VERSION 5.7 ;
  NOWIREEXTENSIONATPIN ON ;
  DIVIDERCHAR "/" ;
  BUSBITCHARS "[]" ;
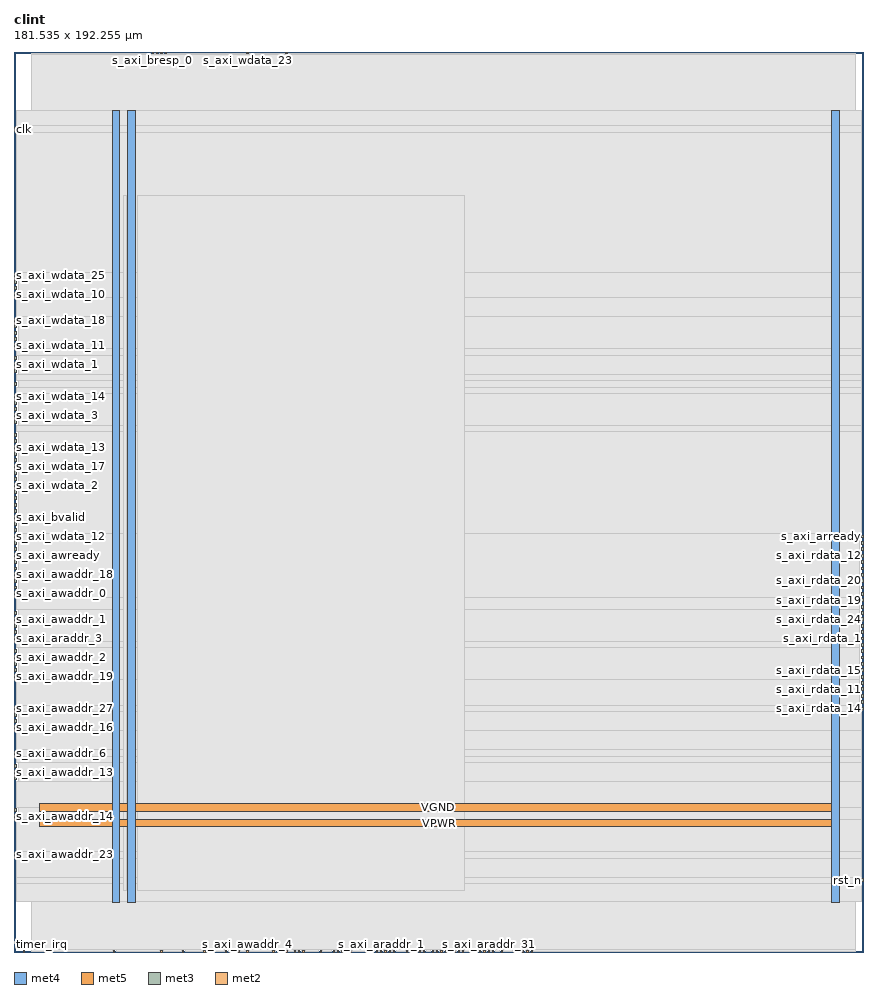
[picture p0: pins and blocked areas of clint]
MACRO clint
  CLASS BLOCK ;
  FOREIGN clint ;
  ORIGIN 0.000 0.000 ;
  SIZE 181.535 BY 192.255 ;
  PIN VGND
    DIRECTION INOUT ;
    USE GROUND ;
    PORT
      LAYER met4 ;
        RECT 24.340 10.640 25.940 179.760 ;
    END
    PORT
      LAYER met5 ;
        RECT 5.520 30.030 175.720 31.630 ;
    END
  END VGND
  PIN VPWR
    DIRECTION INOUT ;
    USE POWER ;
    PORT
      LAYER met4 ;
        RECT 21.040 10.640 22.640 179.760 ;
    END
    PORT
      LAYER met4 ;
        RECT 174.640 10.640 176.240 179.760 ;
    END
    PORT
      LAYER met5 ;
        RECT 5.520 26.730 176.240 28.330 ;
    END
  END VPWR
  PIN clk
    DIRECTION INPUT ;
    USE SIGNAL ;
    ANTENNAGATEAREA 1.286700 ;
    ANTENNADIFFAREA 0.434700 ;
    PORT
      LAYER met3 ;
        RECT 0.000 175.480 0.600 176.080 ;
    END
  END clk
  PIN rst_n
    DIRECTION INPUT ;
    USE SIGNAL ;
    ANTENNAGATEAREA 0.647700 ;
    ANTENNADIFFAREA 0.434700 ;
    PORT
      LAYER met3 ;
        RECT 180.935 15.000 181.535 15.600 ;
    END
  END rst_n
  PIN s_axi_araddr_0
    DIRECTION INPUT ;
    USE SIGNAL ;
    ANTENNAGATEAREA 0.647700 ;
    ANTENNADIFFAREA 0.434700 ;
    PORT
      LAYER met2 ;
        RECT 68.170 0.000 68.450 0.280 ;
    END
  END s_axi_araddr_0
  PIN s_axi_araddr_1
    DIRECTION INPUT ;
    USE SIGNAL ;
    ANTENNAGATEAREA 0.647700 ;
    ANTENNADIFFAREA 0.434700 ;
    PORT
      LAYER met2 ;
        RECT 78.290 0.000 78.570 0.280 ;
    END
  END s_axi_araddr_1
  PIN s_axi_araddr_10
    DIRECTION INPUT ;
    USE SIGNAL ;
    ANTENNAGATEAREA 0.647700 ;
    ANTENNADIFFAREA 0.434700 ;
    PORT
      LAYER met2 ;
        RECT 65.410 0.000 65.690 0.280 ;
    END
  END s_axi_araddr_10
  PIN s_axi_araddr_11
    DIRECTION INPUT ;
    USE SIGNAL ;
    ANTENNAGATEAREA 0.647700 ;
    ANTENNADIFFAREA 0.434700 ;
    PORT
      LAYER met2 ;
        RECT 77.370 0.000 77.650 0.280 ;
    END
  END s_axi_araddr_11
  PIN s_axi_araddr_12
    DIRECTION INPUT ;
    USE SIGNAL ;
    ANTENNAGATEAREA 0.647700 ;
    ANTENNADIFFAREA 0.434700 ;
    PORT
      LAYER met2 ;
        RECT 79.210 0.000 79.490 0.280 ;
    END
  END s_axi_araddr_12
  PIN s_axi_araddr_13
    DIRECTION INPUT ;
    USE SIGNAL ;
    ANTENNAGATEAREA 0.647700 ;
    ANTENNADIFFAREA 0.434700 ;
    PORT
      LAYER met2 ;
        RECT 70.010 0.000 70.290 0.280 ;
    END
  END s_axi_araddr_13
  PIN s_axi_araddr_14
    DIRECTION INPUT ;
    USE SIGNAL ;
    ANTENNAGATEAREA 0.647700 ;
    ANTENNADIFFAREA 0.434700 ;
    PORT
      LAYER met2 ;
        RECT 61.730 0.000 62.010 0.280 ;
    END
  END s_axi_araddr_14
  PIN s_axi_araddr_15
    DIRECTION INPUT ;
    USE SIGNAL ;
    ANTENNAGATEAREA 0.647700 ;
    ANTENNADIFFAREA 0.434700 ;
    PORT
      LAYER met2 ;
        RECT 55.290 0.000 55.570 0.280 ;
    END
  END s_axi_araddr_15
  PIN s_axi_araddr_16
    DIRECTION INPUT ;
    USE SIGNAL ;
    ANTENNAGATEAREA 0.647700 ;
    ANTENNADIFFAREA 0.434700 ;
    PORT
      LAYER met2 ;
        RECT 89.330 0.000 89.610 0.280 ;
    END
  END s_axi_araddr_16
  PIN s_axi_araddr_17
    DIRECTION INPUT ;
    USE SIGNAL ;
    ANTENNAGATEAREA 0.647700 ;
    ANTENNADIFFAREA 0.434700 ;
    PORT
      LAYER met2 ;
        RECT 110.490 0.000 110.770 0.280 ;
    END
  END s_axi_araddr_17
  PIN s_axi_araddr_18
    DIRECTION INPUT ;
    USE SIGNAL ;
    ANTENNAGATEAREA 0.647700 ;
    ANTENNADIFFAREA 0.434700 ;
    PORT
      LAYER met2 ;
        RECT 87.490 0.000 87.770 0.280 ;
    END
  END s_axi_araddr_18
  PIN s_axi_araddr_19
    DIRECTION INPUT ;
    USE SIGNAL ;
    ANTENNAGATEAREA 0.647700 ;
    ANTENNADIFFAREA 0.434700 ;
    PORT
      LAYER met2 ;
        RECT 104.050 0.000 104.330 0.280 ;
    END
  END s_axi_araddr_19
  PIN s_axi_araddr_2
    DIRECTION INPUT ;
    USE SIGNAL ;
    ANTENNAGATEAREA 0.647700 ;
    ANTENNADIFFAREA 0.434700 ;
    PORT
      LAYER met2 ;
        RECT 71.850 0.000 72.130 0.280 ;
    END
  END s_axi_araddr_2
  PIN s_axi_araddr_20
    DIRECTION INPUT ;
    USE SIGNAL ;
    ANTENNAGATEAREA 0.647700 ;
    ANTENNADIFFAREA 0.434700 ;
    PORT
      LAYER met2 ;
        RECT 80.130 0.000 80.410 0.280 ;
    END
  END s_axi_araddr_20
  PIN s_axi_araddr_21
    DIRECTION INPUT ;
    USE SIGNAL ;
    ANTENNAGATEAREA 0.647700 ;
    ANTENNADIFFAREA 0.434700 ;
    PORT
      LAYER met2 ;
        RECT 95.770 0.000 96.050 0.280 ;
    END
  END s_axi_araddr_21
  PIN s_axi_araddr_22
    DIRECTION INPUT ;
    USE SIGNAL ;
    ANTENNAGATEAREA 0.647700 ;
    ANTENNADIFFAREA 0.434700 ;
    PORT
      LAYER met2 ;
        RECT 99.450 0.000 99.730 0.280 ;
    END
  END s_axi_araddr_22
  PIN s_axi_araddr_23
    DIRECTION INPUT ;
    USE SIGNAL ;
    ANTENNAGATEAREA 0.647700 ;
    ANTENNADIFFAREA 0.434700 ;
    PORT
      LAYER met2 ;
        RECT 100.370 0.000 100.650 0.280 ;
    END
  END s_axi_araddr_23
  PIN s_axi_araddr_24
    DIRECTION INPUT ;
    USE SIGNAL ;
    ANTENNAGATEAREA 0.647700 ;
    ANTENNADIFFAREA 0.434700 ;
    PORT
      LAYER met2 ;
        RECT 86.570 0.000 86.850 0.280 ;
    END
  END s_axi_araddr_24
  PIN s_axi_araddr_25
    DIRECTION INPUT ;
    USE SIGNAL ;
    ANTENNAGATEAREA 0.647700 ;
    ANTENNADIFFAREA 0.434700 ;
    PORT
      LAYER met2 ;
        RECT 109.570 0.000 109.850 0.280 ;
    END
  END s_axi_araddr_25
  PIN s_axi_araddr_26
    DIRECTION INPUT ;
    USE SIGNAL ;
    ANTENNAGATEAREA 0.647700 ;
    ANTENNADIFFAREA 0.434700 ;
    PORT
      LAYER met2 ;
        RECT 106.810 0.000 107.090 0.280 ;
    END
  END s_axi_araddr_26
  PIN s_axi_araddr_27
    DIRECTION INPUT ;
    USE SIGNAL ;
    ANTENNAGATEAREA 0.647700 ;
    ANTENNADIFFAREA 0.434700 ;
    PORT
      LAYER met2 ;
        RECT 81.050 0.000 81.330 0.280 ;
    END
  END s_axi_araddr_27
  PIN s_axi_araddr_28
    DIRECTION INPUT ;
    USE SIGNAL ;
    ANTENNAGATEAREA 0.647700 ;
    ANTENNADIFFAREA 0.434700 ;
    PORT
      LAYER met2 ;
        RECT 90.250 0.000 90.530 0.280 ;
    END
  END s_axi_araddr_28
  PIN s_axi_araddr_29
    DIRECTION INPUT ;
    USE SIGNAL ;
    ANTENNAGATEAREA 0.647700 ;
    ANTENNADIFFAREA 0.434700 ;
    PORT
      LAYER met2 ;
        RECT 108.650 0.000 108.930 0.280 ;
    END
  END s_axi_araddr_29
  PIN s_axi_araddr_3
    DIRECTION INPUT ;
    USE SIGNAL ;
    ANTENNAGATEAREA 0.647700 ;
    ANTENNADIFFAREA 0.434700 ;
    PORT
      LAYER met3 ;
        RECT 0.000 66.680 0.600 67.280 ;
    END
  END s_axi_araddr_3
  PIN s_axi_araddr_30
    DIRECTION INPUT ;
    USE SIGNAL ;
    ANTENNAGATEAREA 0.647700 ;
    ANTENNADIFFAREA 0.434700 ;
    PORT
      LAYER met2 ;
        RECT 98.530 0.000 98.810 0.280 ;
    END
  END s_axi_araddr_30
  PIN s_axi_araddr_31
    DIRECTION INPUT ;
    USE SIGNAL ;
    ANTENNAGATEAREA 0.647700 ;
    ANTENNADIFFAREA 0.434700 ;
    PORT
      LAYER met2 ;
        RECT 101.290 0.000 101.570 0.280 ;
    END
  END s_axi_araddr_31
  PIN s_axi_araddr_4
    DIRECTION INPUT ;
    USE SIGNAL ;
    ANTENNAGATEAREA 0.647700 ;
    ANTENNADIFFAREA 0.434700 ;
    PORT
      LAYER met2 ;
        RECT 60.810 0.000 61.090 0.280 ;
    END
  END s_axi_araddr_4
  PIN s_axi_araddr_5
    DIRECTION INPUT ;
    USE SIGNAL ;
    ANTENNAGATEAREA 0.647700 ;
    ANTENNADIFFAREA 0.434700 ;
    PORT
      LAYER met2 ;
        RECT 59.890 0.000 60.170 0.280 ;
    END
  END s_axi_araddr_5
  PIN s_axi_araddr_6
    DIRECTION INPUT ;
    USE SIGNAL ;
    ANTENNAGATEAREA 0.647700 ;
    ANTENNADIFFAREA 0.434700 ;
    PORT
      LAYER met2 ;
        RECT 70.930 0.000 71.210 0.280 ;
    END
  END s_axi_araddr_6
  PIN s_axi_araddr_7
    DIRECTION INPUT ;
    USE SIGNAL ;
    ANTENNAGATEAREA 0.647700 ;
    ANTENNADIFFAREA 0.434700 ;
    PORT
      LAYER met2 ;
        RECT 58.050 0.000 58.330 0.280 ;
    END
  END s_axi_araddr_7
  PIN s_axi_araddr_8
    DIRECTION INPUT ;
    USE SIGNAL ;
    ANTENNAGATEAREA 0.647700 ;
    ANTENNADIFFAREA 0.434700 ;
    PORT
      LAYER met2 ;
        RECT 69.090 0.000 69.370 0.280 ;
    END
  END s_axi_araddr_8
  PIN s_axi_araddr_9
    DIRECTION INPUT ;
    USE SIGNAL ;
    ANTENNAGATEAREA 0.647700 ;
    ANTENNADIFFAREA 0.434700 ;
    PORT
      LAYER met2 ;
        RECT 56.210 0.000 56.490 0.280 ;
    END
  END s_axi_araddr_9
  PIN s_axi_arready
    DIRECTION OUTPUT ;
    USE SIGNAL ;
    ANTENNAGATEAREA 0.434700 ;
    ANTENNADIFFAREA 1.137600 ;
    PORT
      LAYER met3 ;
        RECT 180.935 88.440 181.535 89.040 ;
    END
  END s_axi_arready
  PIN s_axi_arvalid
    DIRECTION INPUT ;
    USE SIGNAL ;
    ANTENNAGATEAREA 0.647700 ;
    ANTENNADIFFAREA 0.434700 ;
    PORT
      LAYER met2 ;
        RECT 92.090 0.000 92.370 0.280 ;
    END
  END s_axi_arvalid
  PIN s_axi_awaddr_0
    DIRECTION INPUT ;
    USE SIGNAL ;
    ANTENNAGATEAREA 0.647700 ;
    ANTENNADIFFAREA 0.434700 ;
    PORT
      LAYER met3 ;
        RECT 0.000 76.200 0.600 76.800 ;
    END
  END s_axi_awaddr_0
  PIN s_axi_awaddr_1
    DIRECTION INPUT ;
    USE SIGNAL ;
    ANTENNAGATEAREA 0.647700 ;
    ANTENNADIFFAREA 0.434700 ;
    PORT
      LAYER met3 ;
        RECT 0.000 70.760 0.600 71.360 ;
    END
  END s_axi_awaddr_1
  PIN s_axi_awaddr_10
    DIRECTION INPUT ;
    USE SIGNAL ;
    ANTENNAGATEAREA 0.647700 ;
    ANTENNADIFFAREA 0.434700 ;
    PORT
      LAYER met2 ;
        RECT 40.570 0.000 40.850 0.280 ;
    END
  END s_axi_awaddr_10
  PIN s_axi_awaddr_11
    DIRECTION INPUT ;
    USE SIGNAL ;
    ANTENNAGATEAREA 0.647700 ;
    ANTENNADIFFAREA 0.434700 ;
    PORT
      LAYER met2 ;
        RECT 35.970 0.000 36.250 0.280 ;
    END
  END s_axi_awaddr_11
  PIN s_axi_awaddr_12
    DIRECTION INPUT ;
    USE SIGNAL ;
    ANTENNAGATEAREA 0.647700 ;
    ANTENNADIFFAREA 0.434700 ;
    PORT
      LAYER met2 ;
        RECT 31.370 0.000 31.650 0.280 ;
    END
  END s_axi_awaddr_12
  PIN s_axi_awaddr_13
    DIRECTION INPUT ;
    USE SIGNAL ;
    ANTENNAGATEAREA 0.647700 ;
    ANTENNADIFFAREA 0.434700 ;
    PORT
      LAYER met3 ;
        RECT 0.000 38.120 0.600 38.720 ;
    END
  END s_axi_awaddr_13
  PIN s_axi_awaddr_14
    DIRECTION INPUT ;
    USE SIGNAL ;
    ANTENNAGATEAREA 0.647700 ;
    ANTENNADIFFAREA 0.434700 ;
    PORT
      LAYER met3 ;
        RECT 0.000 28.600 0.600 29.200 ;
    END
  END s_axi_awaddr_14
  PIN s_axi_awaddr_15
    DIRECTION INPUT ;
    USE SIGNAL ;
    ANTENNAGATEAREA 0.647700 ;
    ANTENNADIFFAREA 0.434700 ;
    PORT
      LAYER met2 ;
        RECT 21.250 0.000 21.530 0.280 ;
    END
  END s_axi_awaddr_15
  PIN s_axi_awaddr_16
    DIRECTION INPUT ;
    USE SIGNAL ;
    ANTENNAGATEAREA 0.647700 ;
    ANTENNADIFFAREA 0.434700 ;
    PORT
      LAYER met3 ;
        RECT 0.000 47.640 0.600 48.240 ;
    END
  END s_axi_awaddr_16
  PIN s_axi_awaddr_17
    DIRECTION INPUT ;
    USE SIGNAL ;
    ANTENNAGATEAREA 0.647700 ;
    ANTENNADIFFAREA 0.434700 ;
    PORT
      LAYER met3 ;
        RECT 0.000 36.760 0.600 37.360 ;
    END
  END s_axi_awaddr_17
  PIN s_axi_awaddr_18
    DIRECTION INPUT ;
    USE SIGNAL ;
    ANTENNAGATEAREA 0.647700 ;
    ANTENNADIFFAREA 0.434700 ;
    PORT
      LAYER met3 ;
        RECT 0.000 78.920 0.600 79.520 ;
    END
  END s_axi_awaddr_18
  PIN s_axi_awaddr_19
    DIRECTION INPUT ;
    USE SIGNAL ;
    ANTENNAGATEAREA 0.647700 ;
    ANTENNADIFFAREA 0.434700 ;
    PORT
      LAYER met3 ;
        RECT 0.000 58.520 0.600 59.120 ;
    END
  END s_axi_awaddr_19
  PIN s_axi_awaddr_2
    DIRECTION INPUT ;
    USE SIGNAL ;
    ANTENNAGATEAREA 0.647700 ;
    ANTENNADIFFAREA 0.434700 ;
    PORT
      LAYER met3 ;
        RECT 0.000 63.960 0.600 64.560 ;
    END
  END s_axi_awaddr_2
  PIN s_axi_awaddr_20
    DIRECTION INPUT ;
    USE SIGNAL ;
    ANTENNAGATEAREA 0.647700 ;
    ANTENNADIFFAREA 0.434700 ;
    PORT
      LAYER met3 ;
        RECT 0.000 68.040 0.600 68.640 ;
    END
  END s_axi_awaddr_20
  PIN s_axi_awaddr_21
    DIRECTION INPUT ;
    USE SIGNAL ;
    ANTENNAGATEAREA 0.647700 ;
    ANTENNADIFFAREA 0.434700 ;
    PORT
      LAYER met3 ;
        RECT 0.000 39.480 0.600 40.080 ;
    END
  END s_axi_awaddr_21
  PIN s_axi_awaddr_22
    DIRECTION INPUT ;
    USE SIGNAL ;
    ANTENNAGATEAREA 0.647700 ;
    ANTENNADIFFAREA 0.434700 ;
    PORT
      LAYER met3 ;
        RECT 0.000 72.120 0.600 72.720 ;
    END
  END s_axi_awaddr_22
  PIN s_axi_awaddr_23
    DIRECTION INPUT ;
    USE SIGNAL ;
    ANTENNAGATEAREA 0.647700 ;
    ANTENNADIFFAREA 0.434700 ;
    PORT
      LAYER met3 ;
        RECT 0.000 20.440 0.600 21.040 ;
    END
  END s_axi_awaddr_23
  PIN s_axi_awaddr_24
    DIRECTION INPUT ;
    USE SIGNAL ;
    ANTENNAGATEAREA 0.647700 ;
    ANTENNADIFFAREA 0.434700 ;
    PORT
      LAYER met3 ;
        RECT 0.000 80.280 0.600 80.880 ;
    END
  END s_axi_awaddr_24
  PIN s_axi_awaddr_25
    DIRECTION INPUT ;
    USE SIGNAL ;
    ANTENNAGATEAREA 0.647700 ;
    ANTENNADIFFAREA 0.434700 ;
    PORT
      LAYER met3 ;
        RECT 0.000 61.240 0.600 61.840 ;
    END
  END s_axi_awaddr_25
  PIN s_axi_awaddr_26
    DIRECTION INPUT ;
    USE SIGNAL ;
    ANTENNAGATEAREA 0.647700 ;
    ANTENNADIFFAREA 0.434700 ;
    PORT
      LAYER met3 ;
        RECT 0.000 69.400 0.600 70.000 ;
    END
  END s_axi_awaddr_26
  PIN s_axi_awaddr_27
    DIRECTION INPUT ;
    USE SIGNAL ;
    ANTENNAGATEAREA 0.647700 ;
    ANTENNADIFFAREA 0.434700 ;
    PORT
      LAYER met3 ;
        RECT 0.000 50.360 0.600 50.960 ;
    END
  END s_axi_awaddr_27
  PIN s_axi_awaddr_28
    DIRECTION INPUT ;
    USE SIGNAL ;
    ANTENNAGATEAREA 0.647700 ;
    ANTENNADIFFAREA 0.434700 ;
    PORT
      LAYER met3 ;
        RECT 0.000 49.000 0.600 49.600 ;
    END
  END s_axi_awaddr_28
  PIN s_axi_awaddr_29
    DIRECTION INPUT ;
    USE SIGNAL ;
    ANTENNAGATEAREA 0.647700 ;
    ANTENNADIFFAREA 0.434700 ;
    PORT
      LAYER met3 ;
        RECT 0.000 59.880 0.600 60.480 ;
    END
  END s_axi_awaddr_29
  PIN s_axi_awaddr_3
    DIRECTION INPUT ;
    USE SIGNAL ;
    ANTENNAGATEAREA 0.647700 ;
    ANTENNADIFFAREA 0.434700 ;
    PORT
      LAYER met3 ;
        RECT 0.000 62.600 0.600 63.200 ;
    END
  END s_axi_awaddr_3
  PIN s_axi_awaddr_30
    DIRECTION INPUT ;
    USE SIGNAL ;
    ANTENNAGATEAREA 0.647700 ;
    ANTENNADIFFAREA 0.434700 ;
    PORT
      LAYER met3 ;
        RECT 0.000 77.560 0.600 78.160 ;
    END
  END s_axi_awaddr_30
  PIN s_axi_awaddr_31
    DIRECTION INPUT ;
    USE SIGNAL ;
    ANTENNAGATEAREA 0.647700 ;
    ANTENNADIFFAREA 0.434700 ;
    PORT
      LAYER met3 ;
        RECT 0.000 29.960 0.600 30.560 ;
    END
  END s_axi_awaddr_31
  PIN s_axi_awaddr_4
    DIRECTION INPUT ;
    USE SIGNAL ;
    ANTENNAGATEAREA 0.647700 ;
    ANTENNADIFFAREA 0.434700 ;
    PORT
      LAYER met2 ;
        RECT 49.770 0.000 50.050 0.280 ;
    END
  END s_axi_awaddr_4
  PIN s_axi_awaddr_5
    DIRECTION INPUT ;
    USE SIGNAL ;
    ANTENNAGATEAREA 0.647700 ;
    ANTENNADIFFAREA 0.434700 ;
    PORT
      LAYER met3 ;
        RECT 0.000 51.720 0.600 52.320 ;
    END
  END s_axi_awaddr_5
  PIN s_axi_awaddr_6
    DIRECTION INPUT ;
    USE SIGNAL ;
    ANTENNAGATEAREA 0.647700 ;
    ANTENNADIFFAREA 0.434700 ;
    PORT
      LAYER met3 ;
        RECT 0.000 42.200 0.600 42.800 ;
    END
  END s_axi_awaddr_6
  PIN s_axi_awaddr_7
    DIRECTION INPUT ;
    USE SIGNAL ;
    ANTENNAGATEAREA 0.647700 ;
    ANTENNADIFFAREA 0.434700 ;
    PORT
      LAYER met2 ;
        RECT 47.930 0.000 48.210 0.280 ;
    END
  END s_axi_awaddr_7
  PIN s_axi_awaddr_8
    DIRECTION INPUT ;
    USE SIGNAL ;
    ANTENNAGATEAREA 0.647700 ;
    ANTENNADIFFAREA 0.434700 ;
    PORT
      LAYER met2 ;
        RECT 45.170 0.000 45.450 0.280 ;
    END
  END s_axi_awaddr_8
  PIN s_axi_awaddr_9
    DIRECTION INPUT ;
    USE SIGNAL ;
    ANTENNAGATEAREA 0.647700 ;
    ANTENNADIFFAREA 0.434700 ;
    PORT
      LAYER met2 ;
        RECT 47.010 0.000 47.290 0.280 ;
    END
  END s_axi_awaddr_9
  PIN s_axi_awready
    DIRECTION OUTPUT ;
    USE SIGNAL ;
    ANTENNAGATEAREA 0.434700 ;
    ANTENNADIFFAREA 1.137600 ;
    PORT
      LAYER met3 ;
        RECT 0.000 84.360 0.600 84.960 ;
    END
  END s_axi_awready
  PIN s_axi_awvalid
    DIRECTION INPUT ;
    USE SIGNAL ;
    ANTENNAGATEAREA 0.647700 ;
    ANTENNADIFFAREA 0.434700 ;
    PORT
      LAYER met3 ;
        RECT 0.000 81.640 0.600 82.240 ;
    END
  END s_axi_awvalid
  PIN s_axi_bready
    DIRECTION INPUT ;
    USE SIGNAL ;
    ANTENNAGATEAREA 0.647700 ;
    ANTENNADIFFAREA 0.434700 ;
    PORT
      LAYER met3 ;
        RECT 0.000 85.720 0.600 86.320 ;
    END
  END s_axi_bready
  PIN s_axi_bresp_0
    DIRECTION OUTPUT ;
    USE SIGNAL ;
    ANTENNAGATEAREA 0.434700 ;
    ANTENNADIFFAREA 0.775300 ;
    PORT
      LAYER met2 ;
        RECT 29.530 191.975 29.810 192.255 ;
    END
  END s_axi_bresp_0
  PIN s_axi_bresp_1
    DIRECTION OUTPUT ;
    USE SIGNAL ;
    ANTENNAGATEAREA 0.434700 ;
    ANTENNADIFFAREA 0.775300 ;
    PORT
      LAYER met2 ;
        RECT 31.370 191.975 31.650 192.255 ;
    END
  END s_axi_bresp_1
  PIN s_axi_bvalid
    DIRECTION OUTPUT ;
    USE SIGNAL ;
    ANTENNAGATEAREA 0.434700 ;
    ANTENNADIFFAREA 1.137600 ;
    PORT
      LAYER met3 ;
        RECT 0.000 92.520 0.600 93.120 ;
    END
  END s_axi_bvalid
  PIN s_axi_rdata_0
    DIRECTION OUTPUT ;
    USE SIGNAL ;
    ANTENNAGATEAREA 0.434700 ;
    ANTENNADIFFAREA 1.137600 ;
    PORT
      LAYER met2 ;
        RECT 83.810 0.000 84.090 0.280 ;
    END
  END s_axi_rdata_0
  PIN s_axi_rdata_1
    DIRECTION OUTPUT ;
    USE SIGNAL ;
    ANTENNAGATEAREA 0.434700 ;
    ANTENNADIFFAREA 1.137600 ;
    PORT
      LAYER met3 ;
        RECT 180.935 66.680 181.535 67.280 ;
    END
  END s_axi_rdata_1
  PIN s_axi_rdata_10
    DIRECTION OUTPUT ;
    USE SIGNAL ;
    ANTENNAGATEAREA 0.434700 ;
    ANTENNADIFFAREA 1.137600 ;
    PORT
      LAYER met3 ;
        RECT 180.935 87.080 181.535 87.680 ;
    END
  END s_axi_rdata_10
  PIN s_axi_rdata_11
    DIRECTION OUTPUT ;
    USE SIGNAL ;
    ANTENNAGATEAREA 0.434700 ;
    ANTENNADIFFAREA 1.137600 ;
    PORT
      LAYER met3 ;
        RECT 180.935 57.160 181.535 57.760 ;
    END
  END s_axi_rdata_11
  PIN s_axi_rdata_12
    DIRECTION OUTPUT ;
    USE SIGNAL ;
    ANTENNAGATEAREA 0.434700 ;
    ANTENNADIFFAREA 1.137600 ;
    PORT
      LAYER met3 ;
        RECT 180.935 84.360 181.535 84.960 ;
    END
  END s_axi_rdata_12
  PIN s_axi_rdata_13
    DIRECTION OUTPUT ;
    USE SIGNAL ;
    ANTENNAGATEAREA 0.434700 ;
    ANTENNADIFFAREA 1.137600 ;
    PORT
      LAYER met3 ;
        RECT 180.935 54.440 181.535 55.040 ;
    END
  END s_axi_rdata_13
  PIN s_axi_rdata_14
    DIRECTION OUTPUT ;
    USE SIGNAL ;
    ANTENNAGATEAREA 0.434700 ;
    ANTENNADIFFAREA 1.137600 ;
    PORT
      LAYER met3 ;
        RECT 180.935 51.720 181.535 52.320 ;
    END
  END s_axi_rdata_14
  PIN s_axi_rdata_15
    DIRECTION OUTPUT ;
    USE SIGNAL ;
    ANTENNAGATEAREA 0.434700 ;
    ANTENNADIFFAREA 1.137600 ;
    PORT
      LAYER met3 ;
        RECT 180.935 59.880 181.535 60.480 ;
    END
  END s_axi_rdata_15
  PIN s_axi_rdata_16
    DIRECTION OUTPUT ;
    USE SIGNAL ;
    ANTENNAGATEAREA 0.434700 ;
    ANTENNADIFFAREA 1.137600 ;
    PORT
      LAYER met3 ;
        RECT 180.935 83.000 181.535 83.600 ;
    END
  END s_axi_rdata_16
  PIN s_axi_rdata_17
    DIRECTION OUTPUT ;
    USE SIGNAL ;
    ANTENNAGATEAREA 0.434700 ;
    ANTENNADIFFAREA 1.137600 ;
    PORT
      LAYER met3 ;
        RECT 180.935 62.600 181.535 63.200 ;
    END
  END s_axi_rdata_17
  PIN s_axi_rdata_18
    DIRECTION OUTPUT ;
    USE SIGNAL ;
    ANTENNAGATEAREA 0.434700 ;
    ANTENNADIFFAREA 1.137600 ;
    PORT
      LAYER met3 ;
        RECT 180.935 53.080 181.535 53.680 ;
    END
  END s_axi_rdata_18
  PIN s_axi_rdata_19
    DIRECTION OUTPUT ;
    USE SIGNAL ;
    ANTENNAGATEAREA 0.434700 ;
    ANTENNADIFFAREA 1.137600 ;
    PORT
      LAYER met3 ;
        RECT 180.935 74.840 181.535 75.440 ;
    END
  END s_axi_rdata_19
  PIN s_axi_rdata_2
    DIRECTION OUTPUT ;
    USE SIGNAL ;
    ANTENNAGATEAREA 0.434700 ;
    ANTENNADIFFAREA 1.137600 ;
    PORT
      LAYER met2 ;
        RECT 84.730 0.000 85.010 0.280 ;
    END
  END s_axi_rdata_2
  PIN s_axi_rdata_20
    DIRECTION OUTPUT ;
    USE SIGNAL ;
    ANTENNAGATEAREA 0.434700 ;
    ANTENNADIFFAREA 1.137600 ;
    PORT
      LAYER met3 ;
        RECT 180.935 77.560 181.535 78.160 ;
    END
  END s_axi_rdata_20
  PIN s_axi_rdata_21
    DIRECTION OUTPUT ;
    USE SIGNAL ;
    ANTENNAGATEAREA 0.434700 ;
    ANTENNADIFFAREA 1.137600 ;
    PORT
      LAYER met3 ;
        RECT 180.935 85.720 181.535 86.320 ;
    END
  END s_axi_rdata_21
  PIN s_axi_rdata_22
    DIRECTION OUTPUT ;
    USE SIGNAL ;
    ANTENNAGATEAREA 0.434700 ;
    ANTENNADIFFAREA 1.137600 ;
    PORT
      LAYER met3 ;
        RECT 180.935 68.040 181.535 68.640 ;
    END
  END s_axi_rdata_22
  PIN s_axi_rdata_23
    DIRECTION OUTPUT ;
    USE SIGNAL ;
    ANTENNAGATEAREA 0.434700 ;
    ANTENNADIFFAREA 1.137600 ;
    PORT
      LAYER met2 ;
        RECT 94.850 0.000 95.130 0.280 ;
    END
  END s_axi_rdata_23
  PIN s_axi_rdata_24
    DIRECTION OUTPUT ;
    USE SIGNAL ;
    ANTENNAGATEAREA 0.434700 ;
    ANTENNADIFFAREA 1.137600 ;
    PORT
      LAYER met3 ;
        RECT 180.935 69.400 181.535 70.000 ;
    END
  END s_axi_rdata_24
  PIN s_axi_rdata_25
    DIRECTION OUTPUT ;
    USE SIGNAL ;
    ANTENNAGATEAREA 0.434700 ;
    ANTENNADIFFAREA 1.137600 ;
    PORT
      LAYER met3 ;
        RECT 180.935 61.240 181.535 61.840 ;
    END
  END s_axi_rdata_25
  PIN s_axi_rdata_26
    DIRECTION OUTPUT ;
    USE SIGNAL ;
    ANTENNAGATEAREA 0.434700 ;
    ANTENNADIFFAREA 1.137600 ;
    PORT
      LAYER met3 ;
        RECT 180.935 78.920 181.535 79.520 ;
    END
  END s_axi_rdata_26
  PIN s_axi_rdata_27
    DIRECTION OUTPUT ;
    USE SIGNAL ;
    ANTENNAGATEAREA 0.434700 ;
    ANTENNADIFFAREA 1.137600 ;
    PORT
      LAYER met3 ;
        RECT 180.935 81.640 181.535 82.240 ;
    END
  END s_axi_rdata_27
  PIN s_axi_rdata_28
    DIRECTION OUTPUT ;
    USE SIGNAL ;
    ANTENNAGATEAREA 0.434700 ;
    ANTENNADIFFAREA 1.137600 ;
    PORT
      LAYER met3 ;
        RECT 180.935 73.480 181.535 74.080 ;
    END
  END s_axi_rdata_28
  PIN s_axi_rdata_29
    DIRECTION OUTPUT ;
    USE SIGNAL ;
    ANTENNAGATEAREA 0.434700 ;
    ANTENNADIFFAREA 1.137600 ;
    PORT
      LAYER met3 ;
        RECT 180.935 65.320 181.535 65.920 ;
    END
  END s_axi_rdata_29
  PIN s_axi_rdata_3
    DIRECTION OUTPUT ;
    USE SIGNAL ;
    ANTENNAGATEAREA 0.434700 ;
    ANTENNADIFFAREA 1.137600 ;
    PORT
      LAYER met3 ;
        RECT 180.935 80.280 181.535 80.880 ;
    END
  END s_axi_rdata_3
  PIN s_axi_rdata_30
    DIRECTION OUTPUT ;
    USE SIGNAL ;
    ANTENNAGATEAREA 0.434700 ;
    ANTENNADIFFAREA 1.137600 ;
    PORT
      LAYER met3 ;
        RECT 180.935 72.120 181.535 72.720 ;
    END
  END s_axi_rdata_30
  PIN s_axi_rdata_31
    DIRECTION OUTPUT ;
    USE SIGNAL ;
    ANTENNAGATEAREA 0.434700 ;
    ANTENNADIFFAREA 1.137600 ;
    PORT
      LAYER met3 ;
        RECT 180.935 58.520 181.535 59.120 ;
    END
  END s_axi_rdata_31
  PIN s_axi_rdata_4
    DIRECTION OUTPUT ;
    USE SIGNAL ;
    ANTENNAGATEAREA 0.434700 ;
    ANTENNADIFFAREA 1.137600 ;
    PORT
      LAYER met3 ;
        RECT 180.935 55.800 181.535 56.400 ;
    END
  END s_axi_rdata_4
  PIN s_axi_rdata_5
    DIRECTION OUTPUT ;
    USE SIGNAL ;
    ANTENNAGATEAREA 0.434700 ;
    ANTENNADIFFAREA 1.137600 ;
    PORT
      LAYER met3 ;
        RECT 180.935 70.760 181.535 71.360 ;
    END
  END s_axi_rdata_5
  PIN s_axi_rdata_6
    DIRECTION OUTPUT ;
    USE SIGNAL ;
    ANTENNAGATEAREA 0.434700 ;
    ANTENNADIFFAREA 1.137600 ;
    PORT
      LAYER met3 ;
        RECT 180.935 76.200 181.535 76.800 ;
    END
  END s_axi_rdata_6
  PIN s_axi_rdata_7
    DIRECTION OUTPUT ;
    USE SIGNAL ;
    ANTENNAGATEAREA 0.434700 ;
    ANTENNADIFFAREA 1.137600 ;
    PORT
      LAYER met2 ;
        RECT 93.930 0.000 94.210 0.280 ;
    END
  END s_axi_rdata_7
  PIN s_axi_rdata_8
    DIRECTION OUTPUT ;
    USE SIGNAL ;
    ANTENNAGATEAREA 0.434700 ;
    ANTENNADIFFAREA 1.137600 ;
    PORT
      LAYER met3 ;
        RECT 180.935 63.960 181.535 64.560 ;
    END
  END s_axi_rdata_8
  PIN s_axi_rdata_9
    DIRECTION OUTPUT ;
    USE SIGNAL ;
    ANTENNAGATEAREA 0.434700 ;
    ANTENNADIFFAREA 1.137600 ;
    PORT
      LAYER met2 ;
        RECT 102.210 0.000 102.490 0.280 ;
    END
  END s_axi_rdata_9
  PIN s_axi_rready
    DIRECTION INPUT ;
    USE SIGNAL ;
    ANTENNAGATEAREA 0.647700 ;
    ANTENNADIFFAREA 0.434700 ;
    PORT
      LAYER met2 ;
        RECT 91.170 0.000 91.450 0.280 ;
    END
  END s_axi_rready
  PIN s_axi_rresp_0
    DIRECTION OUTPUT ;
    USE SIGNAL ;
    ANTENNAGATEAREA 0.434700 ;
    ANTENNADIFFAREA 0.775300 ;
    PORT
      LAYER met2 ;
        RECT 32.290 191.975 32.570 192.255 ;
    END
  END s_axi_rresp_0
  PIN s_axi_rresp_1
    DIRECTION OUTPUT ;
    USE SIGNAL ;
    ANTENNAGATEAREA 0.434700 ;
    ANTENNADIFFAREA 0.775300 ;
    PORT
      LAYER met2 ;
        RECT 30.450 191.975 30.730 192.255 ;
    END
  END s_axi_rresp_1
  PIN s_axi_rvalid
    DIRECTION OUTPUT ;
    USE SIGNAL ;
    ANTENNAGATEAREA 0.434700 ;
    ANTENNADIFFAREA 1.137600 ;
    PORT
      LAYER met2 ;
        RECT 93.010 0.000 93.290 0.280 ;
    END
  END s_axi_rvalid
  PIN s_axi_wdata_0
    DIRECTION INPUT ;
    USE SIGNAL ;
    ANTENNAGATEAREA 0.647700 ;
    ANTENNADIFFAREA 0.434700 ;
    PORT
      LAYER met3 ;
        RECT 0.000 83.000 0.600 83.600 ;
    END
  END s_axi_wdata_0
  PIN s_axi_wdata_1
    DIRECTION INPUT ;
    USE SIGNAL ;
    ANTENNAGATEAREA 0.647700 ;
    ANTENNADIFFAREA 0.434700 ;
    PORT
      LAYER met3 ;
        RECT 0.000 126.520 0.600 127.120 ;
    END
  END s_axi_wdata_1
  PIN s_axi_wdata_10
    DIRECTION INPUT ;
    USE SIGNAL ;
    ANTENNAGATEAREA 0.647700 ;
    ANTENNADIFFAREA 0.434700 ;
    PORT
      LAYER met3 ;
        RECT 0.000 140.120 0.600 140.720 ;
    END
  END s_axi_wdata_10
  PIN s_axi_wdata_11
    DIRECTION INPUT ;
    USE SIGNAL ;
    ANTENNAGATEAREA 0.647700 ;
    ANTENNADIFFAREA 0.434700 ;
    PORT
      LAYER met3 ;
        RECT 0.000 129.240 0.600 129.840 ;
    END
  END s_axi_wdata_11
  PIN s_axi_wdata_12
    DIRECTION INPUT ;
    USE SIGNAL ;
    ANTENNAGATEAREA 0.647700 ;
    ANTENNADIFFAREA 0.434700 ;
    PORT
      LAYER met3 ;
        RECT 0.000 87.080 0.600 87.680 ;
    END
  END s_axi_wdata_12
  PIN s_axi_wdata_13
    DIRECTION INPUT ;
    USE SIGNAL ;
    ANTENNAGATEAREA 0.647700 ;
    ANTENNADIFFAREA 0.434700 ;
    PORT
      LAYER met3 ;
        RECT 0.000 107.480 0.600 108.080 ;
    END
  END s_axi_wdata_13
  PIN s_axi_wdata_14
    DIRECTION INPUT ;
    USE SIGNAL ;
    ANTENNAGATEAREA 0.647700 ;
    ANTENNADIFFAREA 0.434700 ;
    PORT
      LAYER met3 ;
        RECT 0.000 118.360 0.600 118.960 ;
    END
  END s_axi_wdata_14
  PIN s_axi_wdata_15
    DIRECTION INPUT ;
    USE SIGNAL ;
    ANTENNAGATEAREA 0.647700 ;
    ANTENNADIFFAREA 0.434700 ;
    PORT
      LAYER met3 ;
        RECT 0.000 144.200 0.600 144.800 ;
    END
  END s_axi_wdata_15
  PIN s_axi_wdata_16
    DIRECTION INPUT ;
    USE SIGNAL ;
    ANTENNAGATEAREA 0.647700 ;
    ANTENNADIFFAREA 0.434700 ;
    PORT
      LAYER met3 ;
        RECT 0.000 117.000 0.600 117.600 ;
    END
  END s_axi_wdata_16
  PIN s_axi_wdata_17
    DIRECTION INPUT ;
    USE SIGNAL ;
    ANTENNAGATEAREA 0.647700 ;
    ANTENNADIFFAREA 0.434700 ;
    PORT
      LAYER met3 ;
        RECT 0.000 104.760 0.600 105.360 ;
    END
  END s_axi_wdata_17
  PIN s_axi_wdata_18
    DIRECTION INPUT ;
    USE SIGNAL ;
    ANTENNAGATEAREA 0.647700 ;
    ANTENNADIFFAREA 0.434700 ;
    PORT
      LAYER met3 ;
        RECT 0.000 134.680 0.600 135.280 ;
    END
  END s_axi_wdata_18
  PIN s_axi_wdata_19
    DIRECTION INPUT ;
    USE SIGNAL ;
    ANTENNAGATEAREA 0.647700 ;
    ANTENNADIFFAREA 0.434700 ;
    PORT
      LAYER met3 ;
        RECT 0.000 108.840 0.600 109.440 ;
    END
  END s_axi_wdata_19
  PIN s_axi_wdata_2
    DIRECTION INPUT ;
    USE SIGNAL ;
    ANTENNAGATEAREA 0.647700 ;
    ANTENNADIFFAREA 0.434700 ;
    PORT
      LAYER met3 ;
        RECT 0.000 100.680 0.600 101.280 ;
    END
  END s_axi_wdata_2
  PIN s_axi_wdata_20
    DIRECTION INPUT ;
    USE SIGNAL ;
    ANTENNAGATEAREA 0.647700 ;
    ANTENNADIFFAREA 0.434700 ;
    PORT
      LAYER met3 ;
        RECT 0.000 133.320 0.600 133.920 ;
    END
  END s_axi_wdata_20
  PIN s_axi_wdata_21
    DIRECTION INPUT ;
    USE SIGNAL ;
    ANTENNAGATEAREA 0.647700 ;
    ANTENNADIFFAREA 0.434700 ;
    PORT
      LAYER met3 ;
        RECT 0.000 130.600 0.600 131.200 ;
    END
  END s_axi_wdata_21
  PIN s_axi_wdata_22
    DIRECTION INPUT ;
    USE SIGNAL ;
    ANTENNAGATEAREA 0.647700 ;
    ANTENNADIFFAREA 0.434700 ;
    PORT
      LAYER met3 ;
        RECT 0.000 99.320 0.600 99.920 ;
    END
  END s_axi_wdata_22
  PIN s_axi_wdata_23
    DIRECTION INPUT ;
    USE SIGNAL ;
    ANTENNAGATEAREA 0.647700 ;
    ANTENNADIFFAREA 0.434700 ;
    PORT
      LAYER met2 ;
        RECT 49.770 191.975 50.050 192.255 ;
    END
  END s_axi_wdata_23
  PIN s_axi_wdata_24
    DIRECTION INPUT ;
    USE SIGNAL ;
    ANTENNAGATEAREA 0.647700 ;
    ANTENNADIFFAREA 0.434700 ;
    PORT
      LAYER met3 ;
        RECT 0.000 125.160 0.600 125.760 ;
    END
  END s_axi_wdata_24
  PIN s_axi_wdata_25
    DIRECTION INPUT ;
    USE SIGNAL ;
    ANTENNAGATEAREA 0.647700 ;
    ANTENNADIFFAREA 0.434700 ;
    PORT
      LAYER met3 ;
        RECT 0.000 142.840 0.600 143.440 ;
    END
  END s_axi_wdata_25
  PIN s_axi_wdata_26
    DIRECTION INPUT ;
    USE SIGNAL ;
    ANTENNAGATEAREA 0.647700 ;
    ANTENNADIFFAREA 0.434700 ;
    PORT
      LAYER met3 ;
        RECT 0.000 131.960 0.600 132.560 ;
    END
  END s_axi_wdata_26
  PIN s_axi_wdata_27
    DIRECTION INPUT ;
    USE SIGNAL ;
    ANTENNAGATEAREA 0.647700 ;
    ANTENNADIFFAREA 0.434700 ;
    PORT
      LAYER met3 ;
        RECT 0.000 141.480 0.600 142.080 ;
    END
  END s_axi_wdata_27
  PIN s_axi_wdata_28
    DIRECTION INPUT ;
    USE SIGNAL ;
    ANTENNAGATEAREA 0.647700 ;
    ANTENNADIFFAREA 0.434700 ;
    PORT
      LAYER met3 ;
        RECT 0.000 96.600 0.600 97.200 ;
    END
  END s_axi_wdata_28
  PIN s_axi_wdata_29
    DIRECTION INPUT ;
    USE SIGNAL ;
    ANTENNAGATEAREA 0.647700 ;
    ANTENNADIFFAREA 0.434700 ;
    PORT
      LAYER met2 ;
        RECT 58.050 191.975 58.330 192.255 ;
    END
  END s_axi_wdata_29
  PIN s_axi_wdata_3
    DIRECTION INPUT ;
    USE SIGNAL ;
    ANTENNAGATEAREA 0.647700 ;
    ANTENNADIFFAREA 0.434700 ;
    PORT
      LAYER met3 ;
        RECT 0.000 115.640 0.600 116.240 ;
    END
  END s_axi_wdata_3
  PIN s_axi_wdata_30
    DIRECTION INPUT ;
    USE SIGNAL ;
    ANTENNAGATEAREA 0.647700 ;
    ANTENNADIFFAREA 0.434700 ;
    PORT
      LAYER met3 ;
        RECT 0.000 103.400 0.600 104.000 ;
    END
  END s_axi_wdata_30
  PIN s_axi_wdata_31
    DIRECTION INPUT ;
    USE SIGNAL ;
    ANTENNAGATEAREA 0.647700 ;
    ANTENNADIFFAREA 0.434700 ;
    PORT
      LAYER met3 ;
        RECT 0.000 89.800 0.600 90.400 ;
    END
  END s_axi_wdata_31
  PIN s_axi_wdata_4
    DIRECTION INPUT ;
    USE SIGNAL ;
    ANTENNAGATEAREA 0.647700 ;
    ANTENNADIFFAREA 0.434700 ;
    PORT
      LAYER met3 ;
        RECT 0.000 88.440 0.600 89.040 ;
    END
  END s_axi_wdata_4
  PIN s_axi_wdata_5
    DIRECTION INPUT ;
    USE SIGNAL ;
    ANTENNAGATEAREA 0.647700 ;
    ANTENNADIFFAREA 0.434700 ;
    PORT
      LAYER met3 ;
        RECT 0.000 123.800 0.600 124.400 ;
    END
  END s_axi_wdata_5
  PIN s_axi_wdata_6
    DIRECTION INPUT ;
    USE SIGNAL ;
    ANTENNAGATEAREA 0.647700 ;
    ANTENNADIFFAREA 0.434700 ;
    PORT
      LAYER met3 ;
        RECT 0.000 121.080 0.600 121.680 ;
    END
  END s_axi_wdata_6
  PIN s_axi_wdata_7
    DIRECTION INPUT ;
    USE SIGNAL ;
    ANTENNAGATEAREA 0.647700 ;
    ANTENNADIFFAREA 0.434700 ;
    PORT
      LAYER met3 ;
        RECT 0.000 91.160 0.600 91.760 ;
    END
  END s_axi_wdata_7
  PIN s_axi_wdata_8
    DIRECTION INPUT ;
    USE SIGNAL ;
    ANTENNAGATEAREA 0.647700 ;
    ANTENNADIFFAREA 0.434700 ;
    PORT
      LAYER met3 ;
        RECT 0.000 112.920 0.600 113.520 ;
    END
  END s_axi_wdata_8
  PIN s_axi_wdata_9
    DIRECTION INPUT ;
    USE SIGNAL ;
    ANTENNAGATEAREA 0.647700 ;
    ANTENNADIFFAREA 0.434700 ;
    PORT
      LAYER met3 ;
        RECT 0.000 114.280 0.600 114.880 ;
    END
  END s_axi_wdata_9
  PIN s_axi_wready
    DIRECTION OUTPUT ;
    USE SIGNAL ;
    ANTENNAGATEAREA 0.434700 ;
    ANTENNADIFFAREA 1.137600 ;
    PORT
      LAYER met3 ;
        RECT 0.000 95.240 0.600 95.840 ;
    END
  END s_axi_wready
  PIN s_axi_wstrb_0
    DIRECTION INPUT ;
    USE SIGNAL ;
    ANTENNAGATEAREA 0.647700 ;
    ANTENNADIFFAREA 0.434700 ;
    PORT
      LAYER met3 ;
        RECT 0.000 110.200 0.600 110.800 ;
    END
  END s_axi_wstrb_0
  PIN s_axi_wstrb_1
    DIRECTION INPUT ;
    USE SIGNAL ;
    ANTENNAGATEAREA 0.647700 ;
    ANTENNADIFFAREA 0.434700 ;
    PORT
      LAYER met3 ;
        RECT 0.000 102.040 0.600 102.640 ;
    END
  END s_axi_wstrb_1
  PIN s_axi_wstrb_2
    DIRECTION INPUT ;
    USE SIGNAL ;
    ANTENNAGATEAREA 0.647700 ;
    ANTENNADIFFAREA 0.434700 ;
    PORT
      LAYER met3 ;
        RECT 0.000 97.960 0.600 98.560 ;
    END
  END s_axi_wstrb_2
  PIN s_axi_wstrb_3
    DIRECTION INPUT ;
    USE SIGNAL ;
    ANTENNAGATEAREA 0.647700 ;
    ANTENNADIFFAREA 0.434700 ;
    PORT
      LAYER met3 ;
        RECT 0.000 106.120 0.600 106.720 ;
    END
  END s_axi_wstrb_3
  PIN s_axi_wvalid
    DIRECTION INPUT ;
    USE SIGNAL ;
    ANTENNAGATEAREA 0.647700 ;
    ANTENNADIFFAREA 0.434700 ;
    PORT
      LAYER met3 ;
        RECT 0.000 93.880 0.600 94.480 ;
    END
  END s_axi_wvalid
  PIN soft_irq
    DIRECTION OUTPUT ;
    USE SIGNAL ;
    ANTENNAGATEAREA 0.434700 ;
    ANTENNADIFFAREA 1.137600 ;
    PORT
      LAYER met2 ;
        RECT 75.530 0.000 75.810 0.280 ;
    END
  END soft_irq
  PIN timer_irq
    DIRECTION OUTPUT ;
    USE SIGNAL ;
    PORT
      LAYER met2 ;
        RECT 1.930 0.000 2.210 0.280 ;
    END
  END timer_irq
  OBS
      LAYER nwell ;
        RECT 5.330 10.795 175.910 179.605 ;
      LAYER li1 ;
        RECT 5.520 10.795 175.720 179.605 ;
      LAYER met1 ;
        RECT 3.750 9.900 179.790 179.760 ;
      LAYER met2 ;
        RECT 3.770 191.695 29.250 191.975 ;
        RECT 30.090 191.695 30.170 191.975 ;
        RECT 31.010 191.695 31.090 191.975 ;
        RECT 31.930 191.695 32.010 191.975 ;
        RECT 32.850 191.695 49.490 191.975 ;
        RECT 50.330 191.695 57.770 191.975 ;
        RECT 58.610 191.695 179.770 191.975 ;
        RECT 3.770 0.560 179.770 191.695 ;
        RECT 3.770 0.070 20.970 0.560 ;
        RECT 21.810 0.070 31.090 0.560 ;
        RECT 31.930 0.070 35.690 0.560 ;
        RECT 36.530 0.070 40.290 0.560 ;
        RECT 41.130 0.070 44.890 0.560 ;
        RECT 45.730 0.070 46.730 0.560 ;
        RECT 47.570 0.070 47.650 0.560 ;
        RECT 48.490 0.070 49.490 0.560 ;
        RECT 50.330 0.070 55.010 0.560 ;
        RECT 55.850 0.070 55.930 0.560 ;
        RECT 56.770 0.070 57.770 0.560 ;
        RECT 58.610 0.070 59.610 0.560 ;
        RECT 60.450 0.070 60.530 0.560 ;
        RECT 61.370 0.070 61.450 0.560 ;
        RECT 62.290 0.070 65.130 0.560 ;
        RECT 65.970 0.070 67.890 0.560 ;
        RECT 68.730 0.070 68.810 0.560 ;
        RECT 69.650 0.070 69.730 0.560 ;
        RECT 70.570 0.070 70.650 0.560 ;
        RECT 71.490 0.070 71.570 0.560 ;
        RECT 72.410 0.070 75.250 0.560 ;
        RECT 76.090 0.070 77.090 0.560 ;
        RECT 77.930 0.070 78.010 0.560 ;
        RECT 78.850 0.070 78.930 0.560 ;
        RECT 79.770 0.070 79.850 0.560 ;
        RECT 80.690 0.070 80.770 0.560 ;
        RECT 81.610 0.070 83.530 0.560 ;
        RECT 84.370 0.070 84.450 0.560 ;
        RECT 85.290 0.070 86.290 0.560 ;
        RECT 87.130 0.070 87.210 0.560 ;
        RECT 88.050 0.070 89.050 0.560 ;
        RECT 89.890 0.070 89.970 0.560 ;
        RECT 90.810 0.070 90.890 0.560 ;
        RECT 91.730 0.070 91.810 0.560 ;
        RECT 92.650 0.070 92.730 0.560 ;
        RECT 93.570 0.070 93.650 0.560 ;
        RECT 94.490 0.070 94.570 0.560 ;
        RECT 95.410 0.070 95.490 0.560 ;
        RECT 96.330 0.070 98.250 0.560 ;
        RECT 99.090 0.070 99.170 0.560 ;
        RECT 100.010 0.070 100.090 0.560 ;
        RECT 100.930 0.070 101.010 0.560 ;
        RECT 101.850 0.070 101.930 0.560 ;
        RECT 102.770 0.070 103.770 0.560 ;
        RECT 104.610 0.070 106.530 0.560 ;
        RECT 107.370 0.070 108.370 0.560 ;
        RECT 109.210 0.070 109.290 0.560 ;
        RECT 110.130 0.070 110.210 0.560 ;
        RECT 111.050 0.070 179.770 0.560 ;
      LAYER met3 ;
        RECT 0.600 176.480 180.935 179.685 ;
        RECT 1.000 175.080 180.935 176.480 ;
        RECT 0.600 145.200 180.935 175.080 ;
        RECT 1.000 139.720 180.935 145.200 ;
        RECT 0.600 135.680 180.935 139.720 ;
        RECT 1.000 128.840 180.935 135.680 ;
        RECT 0.600 127.520 180.935 128.840 ;
        RECT 1.000 123.400 180.935 127.520 ;
        RECT 0.600 122.080 180.935 123.400 ;
        RECT 1.000 120.680 180.935 122.080 ;
        RECT 0.600 119.360 180.935 120.680 ;
        RECT 1.000 112.520 180.935 119.360 ;
        RECT 0.600 111.200 180.935 112.520 ;
        RECT 1.000 89.440 180.935 111.200 ;
        RECT 1.000 75.800 180.535 89.440 ;
        RECT 0.600 73.120 180.535 75.800 ;
        RECT 1.000 66.280 180.535 73.120 ;
        RECT 0.600 64.960 180.535 66.280 ;
        RECT 1.000 58.120 180.535 64.960 ;
        RECT 0.600 52.720 180.535 58.120 ;
        RECT 1.000 51.320 180.535 52.720 ;
        RECT 1.000 47.240 180.935 51.320 ;
        RECT 0.600 43.200 180.935 47.240 ;
        RECT 1.000 41.800 180.935 43.200 ;
        RECT 0.600 40.480 180.935 41.800 ;
        RECT 1.000 36.360 180.935 40.480 ;
        RECT 0.600 30.960 180.935 36.360 ;
        RECT 1.000 28.200 180.935 30.960 ;
        RECT 0.600 21.440 180.935 28.200 ;
        RECT 1.000 20.040 180.935 21.440 ;
        RECT 0.600 16.000 180.935 20.040 ;
        RECT 0.600 14.600 180.535 16.000 ;
        RECT 0.600 10.715 180.935 14.600 ;
      LAYER met4 ;
        RECT 23.295 13.095 23.940 161.665 ;
        RECT 26.340 13.095 96.305 161.665 ;
  END
END clint
END LIBRARY

